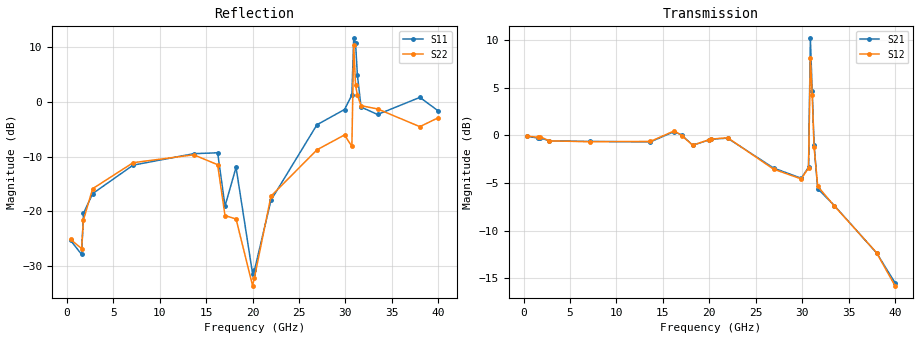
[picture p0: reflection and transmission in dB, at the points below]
! Network Analyzer HP8722ES.07.66: Jul 25, 2000 Serial No. US39175408
! 27 Oct 2004  11:41:20
! Frequency  S11  S21  S12  S22
# HZ  S  DB R  50
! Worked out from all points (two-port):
!   201 points, 400 MHz to 40 GHz, reference 50 ohm
!   highest |S21| = 10.18 dB at 30.89 GHz (marker M1); lowest = -15.4 dB at 40 GHz (marker M2)
!   |S21| within 3 dB of the highest: 30.84806 GHz to 30.99903 GHz (151 MHz wide, 0.488 % of centre)
!   lowest |S11| = -31.4 dB at 20 GHz (marker M3), VSWR 1.06, Z = 50.6 - j2.64 ohm
!   |S11| at or under -10 dB: start of sweep to 8.974 GHz; 16.42 GHz to 24.32 GHz (7.897 GHz wide, 38.8 % of centre)
!   |S22| runs from -34.3 to 10.5 dB; largest |S21 - S12| = 1.4
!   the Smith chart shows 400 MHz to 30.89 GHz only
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4e8  -25.33 -91.0  -0.11 0.6  -0.06 1.0  -25.16 -91.9
1.588e9  -27.90 -90.7  -0.27 -6.0  -0.21 -6.1  -26.83 -72.7
1.786e9  -20.39 -96.1  -0.25 -4.6  -0.14 -4.0  -21.58 -90.0
2.776e9  -16.77 -81.8  -0.58 -6.3  -0.57 -6.2  -15.87 -80.1
7.132e9  -11.56 -108.4  -0.63 -19.5  -0.66 -20.0  -11.11 -105.5
1.3666e10  -9.46 -116.4  -0.68 -33.9  -0.63 -34.1  -9.67 -127.2
1.624e10  -9.30 -125.9  0.41 -39.2  0.48 -40.2  -11.48 -152.5
1.7032e10  -19.05 -98.5  0.04 -53.7  -0.01 -54.8  -20.79 165.6
1.822e10  -11.96 -108.1  -1.03 -47.7  -1.03 -48.4  -21.41 -128.9
2.0002e10  -31.44 -76.5  -0.46 -53.1  -0.44 -54.0  -33.62 -53.2
2.02e10  -30.81 -33.2  -0.38 -53.9  -0.39 -54.8  -32.16 -33.8
2.1982e10  -17.98 16.0  -0.29 -62.8  -0.24 -64.2  -17.24 2.3
2.6932e10  -4.17 35.9  -3.42 -87.0  -3.54 -90.2  -8.76 11.7
2.9902e10  -1.38 17.5  -4.49 -104.9  -4.56 -106.6  -6.03 -16.3
3.0694e10  1.31 2.5  -3.34 -126.8  -3.41 -127.1  -8.13 34.6
3.0892e10  11.64 36.0  10.18 25.6  8.09 0.5  10.48 -57.6
3.109e10  10.84 -0.0  4.63 -22.5  4.26 -24.6  3.14 -42.7
3.1288e10  4.94 -29.5  -1.02 -43.9  -1.17 -46.8  1.23 -27.0
3.1684e10  -0.93 -28.9  -5.59 -74.5  -5.34 -76.8  -0.68 -22.8
3.3466e10  -2.29 -20.2  -7.35 -95.3  -7.39 -97.1  -1.28 -29.2
3.802e10  0.84 -25.5  -12.32 -117.3  -12.30 -121.4  -4.52 -45.4
4e10  -1.64 -40.0  -15.44 -149.6  -15.76 -158.1  -2.88 -46.8
